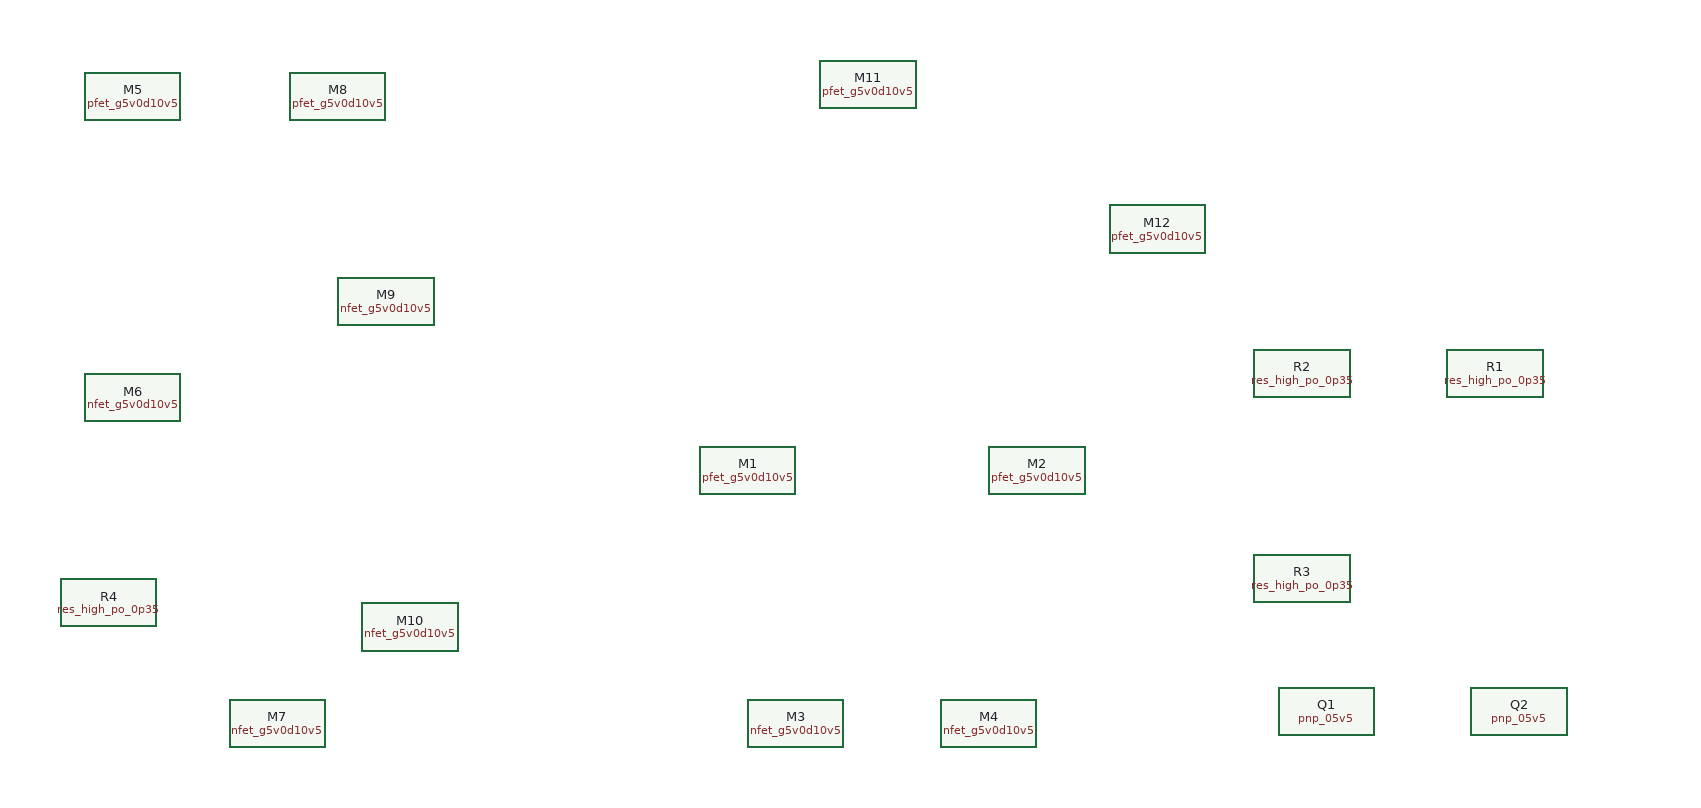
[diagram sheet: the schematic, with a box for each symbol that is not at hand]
v {xschem version=3.4.8RC file_version=1.3}
G {}
K {}
V {}
S {}
F {}
E {}
C {sky130_fd_pr/pfet_g5v0d10v5.sym} 120 -30 0 1 {name=M2
W=1
L=0.5
nf=1
mult=1
ad="expr('int((@nf + 1)/2) * @W / @nf * 0.29')"
pd="expr('2*int((@nf + 1)/2) * (@W / @nf + 0.29)')"
as="expr('int((@nf + 2)/2) * @W / @nf * 0.29')"
ps="expr('2*int((@nf + 2)/2) * (@W / @nf + 0.29)')"
nrd="expr('0.29 / @W ')" nrs="expr('0.29 / @W ')"
sa=0 sb=0 sd=0
model=pfet_g5v0d10v5
spiceprefix=X
}
C {sky130_fd_pr/pfet_g5v0d10v5.sym} -120 -30 0 0 {name=M1
W=1
L=0.5
nf=1
mult=1
ad="expr('int((@nf + 1)/2) * @W / @nf * 0.29')"
pd="expr('2*int((@nf + 1)/2) * (@W / @nf + 0.29)')"
as="expr('int((@nf + 2)/2) * @W / @nf * 0.29')"
ps="expr('2*int((@nf + 2)/2) * (@W / @nf + 0.29)')"
nrd="expr('0.29 / @W ')" nrs="expr('0.29 / @W ')"
sa=0 sb=0 sd=0
model=pfet_g5v0d10v5
spiceprefix=X
}
C {sky130_fd_pr/nfet_g5v0d10v5.sym} -80 180 0 1 {name=M3
W=1
L=0.5
nf=1
mult=1
ad="expr('int((@nf + 1)/2) * @W / @nf * 0.29')"
pd="expr('2*int((@nf + 1)/2) * (@W / @nf + 0.29)')"
as="expr('int((@nf + 2)/2) * @W / @nf * 0.29')"
ps="expr('2*int((@nf + 2)/2) * (@W / @nf + 0.29)')"
nrd="expr('0.29 / @W ')" nrs="expr('0.29 / @W ')"
sa=0 sb=0 sd=0
model=nfet_g5v0d10v5
spiceprefix=X
}
C {sky130_fd_pr/nfet_g5v0d10v5.sym} 80 180 0 0 {name=M4
W=1
L=0.5
nf=1
mult=1
ad="expr('int((@nf + 1)/2) * @W / @nf * 0.29')"
pd="expr('2*int((@nf + 1)/2) * (@W / @nf + 0.29)')"
as="expr('int((@nf + 2)/2) * @W / @nf * 0.29')"
ps="expr('2*int((@nf + 2)/2) * (@W / @nf + 0.29)')"
nrd="expr('0.29 / @W ')" nrs="expr('0.29 / @W ')"
sa=0 sb=0 sd=0
model=nfet_g5v0d10v5
spiceprefix=X
}
C {sky130_fd_pr/pfet_g5v0d10v5.sym} -630 -340 0 1 {name=M5
W=1
L=0.5
nf=1
mult=1
ad="expr('int((@nf + 1)/2) * @W / @nf * 0.29')"
pd="expr('2*int((@nf + 1)/2) * (@W / @nf + 0.29)')"
as="expr('int((@nf + 2)/2) * @W / @nf * 0.29')"
ps="expr('2*int((@nf + 2)/2) * (@W / @nf + 0.29)')"
nrd="expr('0.29 / @W ')" nrs="expr('0.29 / @W ')"
sa=0 sb=0 sd=0
model=pfet_g5v0d10v5
spiceprefix=X
}
C {sky130_fd_pr/nfet_g5v0d10v5.sym} -630 -90 0 1 {name=M6
W=1
L=0.5
nf=1
mult=1
ad="expr('int((@nf + 1)/2) * @W / @nf * 0.29')"
pd="expr('2*int((@nf + 1)/2) * (@W / @nf + 0.29)')"
as="expr('int((@nf + 2)/2) * @W / @nf * 0.29')"
ps="expr('2*int((@nf + 2)/2) * (@W / @nf + 0.29)')"
nrd="expr('0.29 / @W ')" nrs="expr('0.29 / @W ')"
sa=0 sb=0 sd=0
model=nfet_g5v0d10v5
spiceprefix=X
}
C {sky130_fd_pr/nfet_g5v0d10v5.sym} -510 180 0 1 {name=M7
W=1
L=0.5
nf=1
mult=1
ad="expr('int((@nf + 1)/2) * @W / @nf * 0.29')"
pd="expr('2*int((@nf + 1)/2) * (@W / @nf + 0.29)')"
as="expr('int((@nf + 2)/2) * @W / @nf * 0.29')"
ps="expr('2*int((@nf + 2)/2) * (@W / @nf + 0.29)')"
nrd="expr('0.29 / @W ')" nrs="expr('0.29 / @W ')"
sa=0 sb=0 sd=0
model=nfet_g5v0d10v5
spiceprefix=X
}
C {sky130_fd_pr/pfet_g5v0d10v5.sym} -460 -340 0 0 {name=M8
W=1
L=0.5
nf=1
mult=1
ad="expr('int((@nf + 1)/2) * @W / @nf * 0.29')"
pd="expr('2*int((@nf + 1)/2) * (@W / @nf + 0.29)')"
as="expr('int((@nf + 2)/2) * @W / @nf * 0.29')"
ps="expr('2*int((@nf + 2)/2) * (@W / @nf + 0.29)')"
nrd="expr('0.29 / @W ')" nrs="expr('0.29 / @W ')"
sa=0 sb=0 sd=0
model=pfet_g5v0d10v5
spiceprefix=X
}
C {sky130_fd_pr/nfet_g5v0d10v5.sym} -420 -170 0 1 {name=M9
W=1
L=0.5
nf=1
mult=1
ad="expr('int((@nf + 1)/2) * @W / @nf * 0.29')"
pd="expr('2*int((@nf + 1)/2) * (@W / @nf + 0.29)')"
as="expr('int((@nf + 2)/2) * @W / @nf * 0.29')"
ps="expr('2*int((@nf + 2)/2) * (@W / @nf + 0.29)')"
nrd="expr('0.29 / @W ')" nrs="expr('0.29 / @W ')"
sa=0 sb=0 sd=0
model=nfet_g5v0d10v5
spiceprefix=X
}
C {sky130_fd_pr/nfet_g5v0d10v5.sym} -400 100 0 1 {name=M10
W=1
L=0.5
nf=1
mult=1
ad="expr('int((@nf + 1)/2) * @W / @nf * 0.29')"
pd="expr('2*int((@nf + 1)/2) * (@W / @nf + 0.29)')"
as="expr('int((@nf + 2)/2) * @W / @nf * 0.29')"
ps="expr('2*int((@nf + 2)/2) * (@W / @nf + 0.29)')"
nrd="expr('0.29 / @W ')" nrs="expr('0.29 / @W ')"
sa=0 sb=0 sd=0
model=nfet_g5v0d10v5
spiceprefix=X
}
C {sky130_fd_pr/pfet_g5v0d10v5.sym} -20 -350 0 0 {name=M11
W=1
L=0.5
nf=1
mult=1
ad="expr('int((@nf + 1)/2) * @W / @nf * 0.29')"
pd="expr('2*int((@nf + 1)/2) * (@W / @nf + 0.29)')"
as="expr('int((@nf + 2)/2) * @W / @nf * 0.29')"
ps="expr('2*int((@nf + 2)/2) * (@W / @nf + 0.29)')"
nrd="expr('0.29 / @W ')" nrs="expr('0.29 / @W ')"
sa=0 sb=0 sd=0
model=pfet_g5v0d10v5
spiceprefix=X
}
C {sky130_fd_pr/pfet_g5v0d10v5.sym} 220 -230 0 0 {name=M12
W=1
L=0.5
nf=1
mult=1
ad="expr('int((@nf + 1)/2) * @W / @nf * 0.29')"
pd="expr('2*int((@nf + 1)/2) * (@W / @nf + 0.29)')"
as="expr('int((@nf + 2)/2) * @W / @nf * 0.29')"
ps="expr('2*int((@nf + 2)/2) * (@W / @nf + 0.29)')"
nrd="expr('0.29 / @W ')" nrs="expr('0.29 / @W ')"
sa=0 sb=0 sd=0
model=pfet_g5v0d10v5
spiceprefix=X
}
C {sky130_fd_pr/res_high_po_0p35.sym} 500 -110 0 0 {name=R1
L=0.35
model=res_high_po_0p35
spiceprefix=X
mult=1}
C {sky130_fd_pr/res_high_po_0p35.sym} 340 -110 0 0 {name=R2
L=0.35
model=res_high_po_0p35
spiceprefix=X
mult=1}
C {sky130_fd_pr/res_high_po_0p35.sym} 340 60 0 1 {name=R3
L=0.35
model=res_high_po_0p35
spiceprefix=X
mult=1}
C {sky130_fd_pr/res_high_po_0p35.sym} -650 80 0 1 {name=R4
L=0.35
model=res_high_po_0p35
spiceprefix=X
mult=1}
C {sky130_fd_pr/pnp_05v5.sym} 360 170 0 1 {name=Q1
model=pnp_05v5_W3p40L3p40
m=1
spiceprefix=X
}
C {sky130_fd_pr/pnp_05v5.sym} 520 170 0 1 {name=Q2
model=pnp_05v5_W3p40L3p40
m=1
spiceprefix=X
}
